VERSION 5.7 ;
  NOWIREEXTENSIONATPIN ON ;
  DIVIDERCHAR "/" ;
  BUSBITCHARS "[]" ;
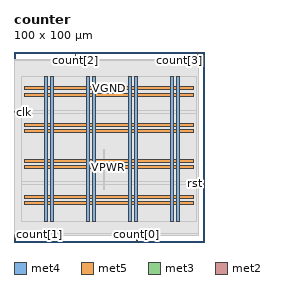
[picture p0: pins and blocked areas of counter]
MACRO counter
  CLASS BLOCK ;
  FOREIGN counter ;
  ORIGIN 0.000 0.000 ;
  SIZE 100.000 BY 100.000 ;
  PIN VGND
    DIRECTION INOUT ;
    USE GROUND ;
    PORT
      LAYER met4 ;
        RECT 19.115 10.640 20.715 87.280 ;
    END
    PORT
      LAYER met4 ;
        RECT 41.310 10.640 42.910 87.280 ;
    END
    PORT
      LAYER met4 ;
        RECT 63.505 10.640 65.105 87.280 ;
    END
    PORT
      LAYER met4 ;
        RECT 85.700 10.640 87.300 87.280 ;
    END
    PORT
      LAYER met5 ;
        RECT 5.280 22.900 94.540 24.500 ;
    END
    PORT
      LAYER met5 ;
        RECT 5.280 41.940 94.540 43.540 ;
    END
    PORT
      LAYER met5 ;
        RECT 5.280 60.980 94.540 62.580 ;
    END
    PORT
      LAYER met5 ;
        RECT 5.280 80.020 94.540 81.620 ;
    END
  END VGND
  PIN VPWR
    DIRECTION INOUT ;
    USE POWER ;
    PORT
      LAYER met4 ;
        RECT 15.815 10.640 17.415 87.280 ;
    END
    PORT
      LAYER met4 ;
        RECT 38.010 10.640 39.610 87.280 ;
    END
    PORT
      LAYER met4 ;
        RECT 60.205 10.640 61.805 87.280 ;
    END
    PORT
      LAYER met4 ;
        RECT 82.400 10.640 84.000 87.280 ;
    END
    PORT
      LAYER met5 ;
        RECT 5.280 19.600 94.540 21.200 ;
    END
    PORT
      LAYER met5 ;
        RECT 5.280 38.640 94.540 40.240 ;
    END
    PORT
      LAYER met5 ;
        RECT 5.280 57.680 94.540 59.280 ;
    END
    PORT
      LAYER met5 ;
        RECT 5.280 76.720 94.540 78.320 ;
    END
  END VPWR
  PIN clk
    DIRECTION INPUT ;
    USE SIGNAL ;
    ANTENNAGATEAREA 0.852000 ;
    PORT
      LAYER met3 ;
        RECT 0.000 68.040 4.000 68.640 ;
    END
  END clk
  PIN count[0]
    DIRECTION OUTPUT TRISTATE ;
    USE SIGNAL ;
    ANTENNADIFFAREA 0.795200 ;
    PORT
      LAYER met2 ;
        RECT 64.490 0.000 64.770 4.000 ;
    END
  END count[0]
  PIN count[1]
    DIRECTION OUTPUT TRISTATE ;
    USE SIGNAL ;
    ANTENNADIFFAREA 0.795200 ;
    PORT
      LAYER met2 ;
        RECT 0.090 0.000 0.370 4.000 ;
    END
  END count[1]
  PIN count[2]
    DIRECTION OUTPUT TRISTATE ;
    USE SIGNAL ;
    ANTENNADIFFAREA 0.795200 ;
    PORT
      LAYER met2 ;
        RECT 32.290 96.000 32.570 100.000 ;
    END
  END count[2]
  PIN count[3]
    DIRECTION OUTPUT TRISTATE ;
    USE SIGNAL ;
    ANTENNADIFFAREA 0.795200 ;
    PORT
      LAYER met2 ;
        RECT 96.690 96.000 96.970 100.000 ;
    END
  END count[3]
  PIN rst
    DIRECTION INPUT ;
    USE SIGNAL ;
    ANTENNAGATEAREA 0.213000 ;
    PORT
      LAYER met3 ;
        RECT 96.000 30.640 100.000 31.240 ;
    END
  END rst
  OBS
      LAYER li1 ;
        RECT 5.520 10.795 94.300 87.125 ;
      LAYER met1 ;
        RECT 0.070 10.640 96.990 87.280 ;
      LAYER met2 ;
        RECT 0.100 95.720 32.010 96.000 ;
        RECT 32.850 95.720 96.410 96.000 ;
        RECT 0.100 4.280 96.960 95.720 ;
        RECT 0.650 3.670 64.210 4.280 ;
        RECT 65.050 3.670 96.960 4.280 ;
      LAYER met3 ;
        RECT 4.000 69.040 96.000 87.205 ;
        RECT 4.400 67.640 96.000 69.040 ;
        RECT 4.000 31.640 96.000 67.640 ;
        RECT 4.000 30.240 95.600 31.640 ;
        RECT 4.000 10.715 96.000 30.240 ;
      LAYER met4 ;
        RECT 47.215 27.375 47.545 48.785 ;
  END
END counter
END LIBRARY

